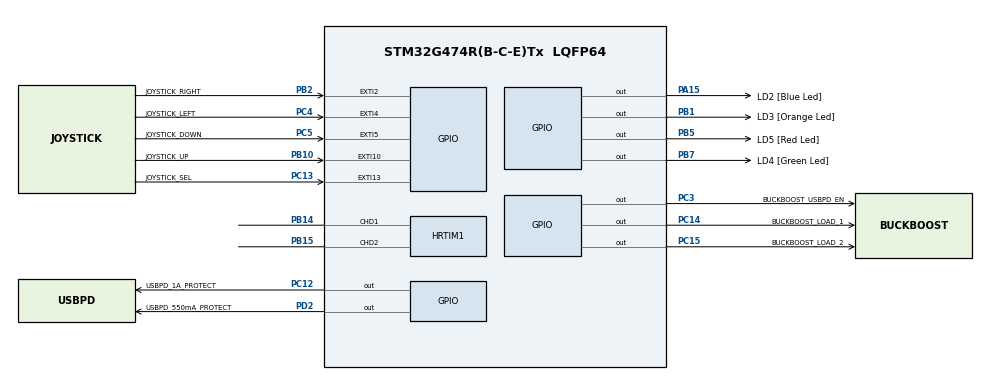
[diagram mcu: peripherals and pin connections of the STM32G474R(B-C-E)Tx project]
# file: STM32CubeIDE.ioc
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HRTIM1.CompareUnit1-Output_TD1TD2=HRTIM_COMPAREUNIT_1
HRTIM1.CompareUnit2-Output_TD1TD2=HRTIM_COMPAREUNIT_2
HRTIM1.CompareUnit3-Output_TD1TD2=HRTIM_COMPAREUNIT_3
HRTIM1.CompareValue1-Output_TD1TD2=544
HRTIM1.CompareValue2-Output_TD1TD2=544
HRTIM1.CompareValue3-Output_TD1TD2=1088
HRTIM1.NumberResetSource1-Output_TD1TD2=1
HRTIM1.NumberResetSource2_TD=1
HRTIM1.NumberSetSource1-Output_TD1TD2=1
HRTIM1.Periode_TD=5440
HRTIM1.ResetOutput1_Source1-Output_TD1TD2=HRTIM_OUTPUTRESET_TIMCMP1
HRTIM1.ResetOutput2_Source1-Output_TD1TD2=HRTIM_OUTPUTRESET_TIMCMP3
HRTIM1.SetOutput1_Source1-Output_TD1TD2=HRTIM_OUTPUTSET_TIMPER
Mcu.Family=STM32G4
Mcu.Name=STM32G474R(B-C-E)Tx
Mcu.Package=LQFP64
NVIC.EXTI15_10_IRQn=true\:0\:0\:false\:false\:true\:true\:true\:true
NVIC.EXTI2_IRQn=true\:0\:0\:false\:false\:true\:true\:true\:true
NVIC.EXTI4_IRQn=true\:0\:0\:false\:false\:true\:true\:true\:true
NVIC.EXTI9_5_IRQn=true\:0\:0\:false\:false\:true\:true\:true\:true
NVIC.PriorityGroup=NVIC_PRIORITYGROUP_4
PA0.GPIO_Label=BUCK_GREEN_SENSE
PA0.Signal=COMP3_INP
PA1.GPIO_Label=BUCKBOOST_VIN
PA1.Signal=ADC1_IN2
PA10.Signal=UCPD1_DBCC2
PA11.Signal=USB_DM
PA12.Signal=USB_DP
PA13.Mode=Serial_Wire
PA13.Signal=SYS_JTMS-SWDIO
PA14.Mode=Serial_Wire
PA14.Signal=SYS_JTCK-SWCLK
PA15.GPIO_Label=LD2 [Blue Led]
PA15.Signal=GPIO_Output
PA2.GPIO_Label=BUCKBOOST_I_IN_AVG
PA2.Signal=ADC1_IN3
PA3.GPIO_Label=BUCKBOOST_VOUT
PA3.Signal=ADC1_IN4
PA7.GPIO_Label=BUCK_RED_SENSE
PA7.Signal=COMP2_INP
PA8.GPIO_Label=BUCK_BLUE_DRIVE
PA8.Signal=HRTIM1_CHA1
PA9.Signal=UCPD1_DBCC1
PB0.GPIO_Label=BUCK_BLUE_SENSE
PB0.Signal=COMP4_INP
PB1.GPIO_Label=LD3 [Orange Led]
PB1.Signal=GPIO_Output
PB10.GPIO_Label=JOYSTICK_UP
PB10.GPIO_PuPd=GPIO_PULLUP
PB10.Signal=GPXTI10
PB11.GPIO_Label=BUCKBOOST_I_IN_SENSE
PB11.Signal=COMP6_INP
PB12.GPIO_Label=BUCKBOOST_P1_DRIVE
PB12.Signal=HRTIM1_CHC1
PB13.GPIO_Label=BUCKBOOST_N1_DRIVE
PB13.Signal=HRTIM1_CHC2
PB14.GPIO_Mode=GPIO_MODE_AF_PP
PB14.GPIO_PuPd=GPIO_NOPULL
PB14.GPIO_Speed_High_Default=GPIO_SPEED_FREQ_VERY_HIGH
PB14.Mode=Output_TD1TD2
PB14.Signal=HRTIM1_CHD1
PB15.Mode=Output_TD1TD2
PB15.Signal=HRTIM1_CHD2
PB2.GPIO_Label=JOYSTICK_RIGHT
PB2.GPIO_PuPd=GPIO_PULLUP
PB2.Signal=GPXTI2
PB3.Signal=SYS_JTDO-SWO
PB4.Signal=UCPD1_CC2
PB5.GPIO_Label=LD5 [Red Led]
PB5.Signal=GPIO_Output
PB6.Signal=UCPD1_CC1
PB7.GPIO_Label=LD4 [Green Led]
PB7.Signal=GPIO_Output
PC10.GPIO_Label=USART3_TX[STLINK_TX]
PC10.GPIO_Speed=GPIO_SPEED_FREQ_MEDIUM
PC10.Signal=USART3_TX
PC11.GPIO_Label=USART3_RX[STLINK_RX]
PC11.GPIO_Speed=GPIO_SPEED_FREQ_MEDIUM
PC11.Signal=USART3_RX
PC12.GPIO_Label=USBPD_1A_PROTECT
PC12.Signal=GPIO_Output
PC13.GPIO_Label=JOYSTICK_SEL
PC13.GPIO_PuPd=GPIO_PULLUP
PC13.Signal=GPXTI13
PC14-OSC32_IN.GPIO_Label=BUCKBOOST_LOAD_1
PC14-OSC32_IN.Signal=GPIO_Output
PC15-OSC32_OUT.GPIO_Label=BUCKBOOST_LOAD_2
PC15-OSC32_OUT.Signal=GPIO_Output
PC2.GPIO_Label=USBPD_VIN
PC2.Signal=ADC1_IN8
PC3.GPIO_Label=BUCKBOOST_USBPD_EN
PC3.Signal=GPIO_Output
PC4.GPIO_Label=JOYSTICK_LEFT
PC4.GPIO_PuPd=GPIO_PULLUP
PC4.Signal=GPXTI4
PC5.GPIO_Label=JOYSTICK_DOWN
PC5.GPIO_PuPd=GPIO_PULLUP
PC5.Signal=GPXTI5
PC6.GPIO_Label=BUCK_RED_DRIVE
PC6.Signal=HRTIM1_CHF1
PC7.GPIO_Label=RC_TP4
PC7.Signal=HRTIM1_CHF2
PC8.GPIO_Label=BUCK_GREEN_DRIVE
PC8.Signal=HRTIM1_CHE1
PD2.GPIO_Label=USBPD_550mA_PROTECT
PD2.Signal=GPIO_Output
ProjectManager.HeapSize=0x200
ProjectManager.StackSize=0x400
ProjectManager.TargetToolchain=STM32CubeIDE
RCC.ADC12Freq_Value=170000000
RCC.ADC345Freq_Value=170000000
RCC.AHBFreq_Value=170000000
RCC.APB1Freq_Value=170000000
RCC.APB1TimFreq_Value=170000000
RCC.APB2Freq_Value=170000000
RCC.APB2TimFreq_Value=170000000
RCC.CK48CLockSelection=RCC_USBCLKSOURCE_HSI48
RCC.CortexFreq_Value=170000000
RCC.EXTERNAL_CLOCK_VALUE=12288000
RCC.HCLKFreq_Value=170000000
RCC.HSE_VALUE=8000000
RCC.HSI48_VALUE=48000000
RCC.HSI_VALUE=16000000
RCC.LSE_VALUE=32768
RCC.PLLM=RCC_PLLM_DIV4
RCC.PLLN=85
RCC.PLLP=RCC_PLLP_DIV8
RCC.PLLQ=RCC_PLLQ_DIV8
RCC.SYSCLKFreq_VALUE=170000000
RCC.SYSCLKSource=RCC_SYSCLKSOURCE_PLLCLK
RCC.USBFreq_Value=48000000
RCC.VCOOutputFreq_Value=340000000
VP_SYS_VS_DBSignals.Mode=DisableDeadBatterySignals
board=B-G474E-DPOW1

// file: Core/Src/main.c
/* USER CODE BEGIN Header */
/**
  ******************************************************************************
  * @file           : main.c
  * @brief          : Main program body
  ******************************************************************************
  * @attention
  *
  * Copyright (c) 2026 STMicroelectronics.
  * All rights reserved.
  *
  * This software is licensed under terms that can be found in the LICENSE file
  * in the root directory of this software component.
  * If no LICENSE file comes with this software, it is provided AS-IS.
  *
  ******************************************************************************
  */
/* USER CODE END Header */
#include "main.h"

/* USER CODE BEGIN PD */
/*
 * Timing profile:
 * - HRTIM_TIMING_PROFILE_MAX_RES: 170 MHz x 32 = 183.824 ps/tick
 * - HRTIM_TIMING_PROFILE_500PS:   125 MHz x 16 = 500 ps/tick
 * - HRTIM_TIMING_PROFILE_250PS:   125 MHz x 32 = 250 ps/tick
 */
#define HRTIM_TIMING_PROFILE_MAX_RES  0U
#define HRTIM_TIMING_PROFILE_500PS    1U
#define HRTIM_TIMING_PROFILE_250PS    2U
#define HRTIM_TIMING_PROFILE          HRTIM_TIMING_PROFILE_500PS

#if (HRTIM_TIMING_PROFILE == HRTIM_TIMING_PROFILE_MAX_RES)
#define HRTIM_PLLN_VALUE        85U
#define HRTIM_PLLR_VALUE        RCC_PLLR_DIV2
#define HRTIM_TIMER_PRESCALER   HRTIM_PRESCALERRATIO_MUL32
#define HRTIM_PERIOD_TICK       5440U
#define HRTIM_100NS_TICK        544U
#elif (HRTIM_TIMING_PROFILE == HRTIM_TIMING_PROFILE_500PS)
#define HRTIM_PLLN_VALUE        125U
#define HRTIM_PLLR_VALUE        RCC_PLLR_DIV4
#define HRTIM_TIMER_PRESCALER   HRTIM_PRESCALERRATIO_MUL16
#define HRTIM_PERIOD_TICK       2000U
#define HRTIM_100NS_TICK        200U
#elif (HRTIM_TIMING_PROFILE == HRTIM_TIMING_PROFILE_250PS)
#define HRTIM_PLLN_VALUE        125U
#define HRTIM_PLLR_VALUE        RCC_PLLR_DIV4
#define HRTIM_TIMER_PRESCALER   HRTIM_PRESCALERRATIO_MUL32
#define HRTIM_PERIOD_TICK       4000U
#define HRTIM_100NS_TICK        400U
#else
#error "Unsupported HRTIM_TIMING_PROFILE"
#endif

#define TD1_WIDTH_TICK          HRTIM_100NS_TICK
#define TD1_RISE_TICK           ((HRTIM_PERIOD_TICK / 2U) - (TD1_WIDTH_TICK / 2U))
#define TD1_FALL_TICK           (TD1_RISE_TICK + TD1_WIDTH_TICK)
#define TD2_WIDTH_TICK          TD1_WIDTH_TICK
#define TD2_DELAY_INITIAL_TICK  0U
#define TD2_DELAY_STEP_TICK     1U
#define TD2_DELAY_MAX_TICK      (HRTIM_PERIOD_TICK - TD1_FALL_TICK - TD2_WIDTH_TICK)
#define JOYSTICK_DEBOUNCE_MS    200U
#define JOYSTICK_SETTLE_MS      2U
/* USER CODE END PD */

HRTIM_HandleTypeDef hhrtim1;

/* USER CODE BEGIN PV */
static volatile uint16_t td2_delay_tick = TD2_DELAY_INITIAL_TICK;
static volatile int8_t pending_delay_step = 0;
static volatile uint8_t pending_delay_reset = 0U;
/* USER CODE END PV */

void SystemClock_Config(void);
static void MX_GPIO_Init(void);
static void MX_HRTIM1_Init(void);
/* USER CODE BEGIN PFP */
static void Apply_TD2_Delay(void);
static void Process_Joystick_Command(void);
/* USER CODE END PFP */

/* USER CODE BEGIN 0 */
static void Apply_TD2_Delay(void)
{
  uint32_t cmp3 = TD1_FALL_TICK + td2_delay_tick;
  uint32_t cmp4 = cmp3 + TD2_WIDTH_TICK;

  __HAL_HRTIM_SETCOMPARE(&hhrtim1, HRTIM_TIMERINDEX_TIMER_D, HRTIM_COMPAREUNIT_3, cmp3);
  __HAL_HRTIM_SETCOMPARE(&hhrtim1, HRTIM_TIMERINDEX_TIMER_D, HRTIM_COMPAREUNIT_4, cmp4);
}

static void Process_Joystick_Command(void)
{
  int8_t step;
  uint8_t reset;

  __disable_irq();
  step = pending_delay_step;
  reset = pending_delay_reset;
  pending_delay_step = 0;
  pending_delay_reset = 0U;
  __enable_irq();

  if (reset != 0U)
  {
    td2_delay_tick = TD2_DELAY_INITIAL_TICK;
    Apply_TD2_Delay();
    HAL_Delay(JOYSTICK_SETTLE_MS);
    return;
  }

  if (step > 0)
  {
    if ((td2_delay_tick + TD2_DELAY_STEP_TICK) < TD2_DELAY_MAX_TICK)
    {
      td2_delay_tick += TD2_DELAY_STEP_TICK;
    }
    else
    {
      td2_delay_tick = TD2_DELAY_MAX_TICK;
    }
    Apply_TD2_Delay();
    HAL_Delay(JOYSTICK_SETTLE_MS);
  }
  else if (step < 0)
  {
    if (td2_delay_tick > TD2_DELAY_STEP_TICK)
    {
      td2_delay_tick -= TD2_DELAY_STEP_TICK;
    }
    else
    {
      td2_delay_tick = 0U;
    }
    Apply_TD2_Delay();
    HAL_Delay(JOYSTICK_SETTLE_MS);
  }
}
/* USER CODE END 0 */

int main(void)
{

  /* MCU Configuration--------------------------------------------------------*/

  /* Reset of all peripherals, Initializes the Flash interface and the Systick. */
  HAL_Init();

  /* Configure the system clock */
  SystemClock_Config();

  /* Initialize all configured peripherals */
  MX_GPIO_Init();
  MX_HRTIM1_Init();
  /* USER CODE BEGIN 2 */
  if (HAL_HRTIM_WaveformOutputStart(&hhrtim1, HRTIM_OUTPUT_TD1 | HRTIM_OUTPUT_TD2) != HAL_OK)
  {
    Error_Handler();
  }
  if (HAL_HRTIM_WaveformCountStart(&hhrtim1, HRTIM_TIMERID_TIMER_D) != HAL_OK)
  {
    Error_Handler();
  }
  /* USER CODE END 2 */

  /* Infinite loop */
  while (1)
  {

    /* USER CODE BEGIN 3 */
    Process_Joystick_Command();
  }
  /* USER CODE END 3 */
}

void SystemClock_Config(void)
{
  RCC_OscInitTypeDef RCC_OscInitStruct = {0};
  RCC_ClkInitTypeDef RCC_ClkInitStruct = {0};

  /** Configure the main internal regulator output voltage
  */
  HAL_PWREx_ControlVoltageScaling(PWR_REGULATOR_VOLTAGE_SCALE1_BOOST);

  /** Initializes the RCC Oscillators according to the specified parameters
  * in the RCC_OscInitTypeDef structure.
  */
  RCC_OscInitStruct.OscillatorType = RCC_OSCILLATORTYPE_HSI;
  RCC_OscInitStruct.HSIState = RCC_HSI_ON;
  RCC_OscInitStruct.HSICalibrationValue = RCC_HSICALIBRATION_DEFAULT;
  RCC_OscInitStruct.PLL.PLLState = RCC_PLL_ON;
  RCC_OscInitStruct.PLL.PLLSource = RCC_PLLSOURCE_HSI;
  RCC_OscInitStruct.PLL.PLLM = RCC_PLLM_DIV4;
  RCC_OscInitStruct.PLL.PLLN = HRTIM_PLLN_VALUE;
  RCC_OscInitStruct.PLL.PLLP = RCC_PLLP_DIV8;
  RCC_OscInitStruct.PLL.PLLQ = RCC_PLLQ_DIV8;
  RCC_OscInitStruct.PLL.PLLR = HRTIM_PLLR_VALUE;
  if (HAL_RCC_OscConfig(&RCC_OscInitStruct) != HAL_OK)
  {
    Error_Handler();
  }

  /** Initializes the CPU, AHB and APB buses clocks
  */
  RCC_ClkInitStruct.ClockType = RCC_CLOCKTYPE_HCLK|RCC_CLOCKTYPE_SYSCLK
                              |RCC_CLOCKTYPE_PCLK1|RCC_CLOCKTYPE_PCLK2;
  RCC_ClkInitStruct.SYSCLKSource = RCC_SYSCLKSOURCE_PLLCLK;
  RCC_ClkInitStruct.AHBCLKDivider = RCC_SYSCLK_DIV1;
  RCC_ClkInitStruct.APB1CLKDivider = RCC_HCLK_DIV1;
  RCC_ClkInitStruct.APB2CLKDivider = RCC_HCLK_DIV1;

  if (HAL_RCC_ClockConfig(&RCC_ClkInitStruct, FLASH_LATENCY_4) != HAL_OK)
  {
    Error_Handler();
  }
}

static void MX_HRTIM1_Init(void)
{

  HRTIM_TimeBaseCfgTypeDef pTimeBaseCfg = {0};
  HRTIM_TimerCtlTypeDef pTimerCtl = {0};
  HRTIM_TimerCfgTypeDef pTimerCfg = {0};
  HRTIM_CompareCfgTypeDef pCompareCfg = {0};
  HRTIM_OutputCfgTypeDef pOutputCfg = {0};

  hhrtim1.Instance = HRTIM1;
  hhrtim1.Init.HRTIMInterruptResquests = HRTIM_IT_NONE;
  hhrtim1.Init.SyncOptions = HRTIM_SYNCOPTION_NONE;
  if (HAL_HRTIM_Init(&hhrtim1) != HAL_OK)
  {
    Error_Handler();
  }
  if (HAL_HRTIM_DLLCalibrationStart(&hhrtim1, HRTIM_CALIBRATIONRATE_3) != HAL_OK)
  {
    Error_Handler();
  }
  if (HAL_HRTIM_PollForDLLCalibration(&hhrtim1, 10) != HAL_OK)
  {
    Error_Handler();
  }
  pTimeBaseCfg.Period = HRTIM_PERIOD_TICK;
  pTimeBaseCfg.RepetitionCounter = 0x00;
  pTimeBaseCfg.PrescalerRatio = HRTIM_TIMER_PRESCALER;
  pTimeBaseCfg.Mode = HRTIM_MODE_CONTINUOUS;
  if (HAL_HRTIM_TimeBaseConfig(&hhrtim1, HRTIM_TIMERINDEX_TIMER_D, &pTimeBaseCfg) != HAL_OK)
  {
    Error_Handler();
  }
  pTimerCtl.UpDownMode = HRTIM_TIMERUPDOWNMODE_UP;
  pTimerCtl.TrigHalf = HRTIM_TIMERTRIGHALF_DISABLED;
  pTimerCtl.GreaterCMP3 = HRTIM_TIMERGTCMP3_EQUAL;
  pTimerCtl.GreaterCMP1 = HRTIM_TIMERGTCMP1_EQUAL;
  pTimerCtl.DualChannelDacEnable = HRTIM_TIMER_DCDE_DISABLED;
  if (HAL_HRTIM_WaveformTimerControl(&hhrtim1, HRTIM_TIMERINDEX_TIMER_D, &pTimerCtl) != HAL_OK)
  {
    Error_Handler();
  }
  pTimerCfg.InterruptRequests = HRTIM_TIM_IT_NONE;
  pTimerCfg.DMARequests = HRTIM_TIM_DMA_NONE;
  pTimerCfg.DMASrcAddress = 0x0000;
  pTimerCfg.DMADstAddress = 0x0000;
  pTimerCfg.DMASize = 0x1;
  pTimerCfg.HalfModeEnable = HRTIM_HALFMODE_DISABLED;
  pTimerCfg.InterleavedMode = HRTIM_INTERLEAVED_MODE_DISABLED;
  pTimerCfg.StartOnSync = HRTIM_SYNCSTART_DISABLED;
  pTimerCfg.ResetOnSync = HRTIM_SYNCRESET_DISABLED;
  pTimerCfg.DACSynchro = HRTIM_DACSYNC_NONE;
  pTimerCfg.PreloadEnable = HRTIM_PRELOAD_DISABLED;
  pTimerCfg.UpdateGating = HRTIM_UPDATEGATING_INDEPENDENT;
  pTimerCfg.BurstMode = HRTIM_TIMERBURSTMODE_MAINTAINCLOCK;
  pTimerCfg.RepetitionUpdate = HRTIM_UPDATEONREPETITION_DISABLED;
  pTimerCfg.PushPull = HRTIM_TIMPUSHPULLMODE_DISABLED;
  pTimerCfg.FaultEnable = HRTIM_TIMFAULTENABLE_NONE;
  pTimerCfg.FaultLock = HRTIM_TIMFAULTLOCK_READWRITE;
  pTimerCfg.DeadTimeInsertion = HRTIM_TIMDEADTIMEINSERTION_DISABLED;
  pTimerCfg.DelayedProtectionMode = HRTIM_TIMER_D_E_DELAYEDPROTECTION_DISABLED;
  pTimerCfg.UpdateTrigger = HRTIM_TIMUPDATETRIGGER_NONE;
  pTimerCfg.ResetTrigger = HRTIM_TIMRESETTRIGGER_NONE;
  pTimerCfg.ResetUpdate = HRTIM_TIMUPDATEONRESET_DISABLED;
  pTimerCfg.ReSyncUpdate = HRTIM_TIMERESYNC_UPDATE_UNCONDITIONAL;
  if (HAL_HRTIM_WaveformTimerConfig(&hhrtim1, HRTIM_TIMERINDEX_TIMER_D, &pTimerCfg) != HAL_OK)
  {
    Error_Handler();
  }
  pCompareCfg.CompareValue = TD1_RISE_TICK;
  if (HAL_HRTIM_WaveformCompareConfig(&hhrtim1, HRTIM_TIMERINDEX_TIMER_D, HRTIM_COMPAREUNIT_1, &pCompareCfg) != HAL_OK)
  {
    Error_Handler();
  }
  pCompareCfg.AutoDelayedMode = HRTIM_AUTODELAYEDMODE_REGULAR;
  pCompareCfg.AutoDelayedTimeout = 0x0000;
  pCompareCfg.CompareValue = TD1_FALL_TICK;

  if (HAL_HRTIM_WaveformCompareConfig(&hhrtim1, HRTIM_TIMERINDEX_TIMER_D, HRTIM_COMPAREUNIT_2, &pCompareCfg) != HAL_OK)
  {
    Error_Handler();
  }
  pCompareCfg.CompareValue = TD1_FALL_TICK + td2_delay_tick;
  if (HAL_HRTIM_WaveformCompareConfig(&hhrtim1, HRTIM_TIMERINDEX_TIMER_D, HRTIM_COMPAREUNIT_3, &pCompareCfg) != HAL_OK)
  {
    Error_Handler();
  }
  pCompareCfg.CompareValue = TD1_FALL_TICK + td2_delay_tick + TD2_WIDTH_TICK;
  if (HAL_HRTIM_WaveformCompareConfig(&hhrtim1, HRTIM_TIMERINDEX_TIMER_D, HRTIM_COMPAREUNIT_4, &pCompareCfg) != HAL_OK)
  {
    Error_Handler();
  }
  pOutputCfg.Polarity = HRTIM_OUTPUTPOLARITY_HIGH;
  pOutputCfg.SetSource = HRTIM_OUTPUTSET_TIMCMP1;
  pOutputCfg.ResetSource = HRTIM_OUTPUTRESET_TIMCMP2;
  pOutputCfg.IdleMode = HRTIM_OUTPUTIDLEMODE_NONE;
  pOutputCfg.IdleLevel = HRTIM_OUTPUTIDLELEVEL_INACTIVE;
  pOutputCfg.FaultLevel = HRTIM_OUTPUTFAULTLEVEL_NONE;
  pOutputCfg.ChopperModeEnable = HRTIM_OUTPUTCHOPPERMODE_DISABLED;
  pOutputCfg.BurstModeEntryDelayed = HRTIM_OUTPUTBURSTMODEENTRY_REGULAR;
  if (HAL_HRTIM_WaveformOutputConfig(&hhrtim1, HRTIM_TIMERINDEX_TIMER_D, HRTIM_OUTPUT_TD1, &pOutputCfg) != HAL_OK)
  {
    Error_Handler();
  }
  pOutputCfg.SetSource = HRTIM_OUTPUTSET_NONE;
  pOutputCfg.ResetSource = HRTIM_OUTPUTRESET_TIMCMP3;
  if (HAL_HRTIM_WaveformOutputConfig(&hhrtim1, HRTIM_TIMERINDEX_TIMER_D, HRTIM_OUTPUT_TD2, &pOutputCfg) != HAL_OK)
  {
    Error_Handler();
  }
  /* USER CODE BEGIN HRTIM1_Init 2 */
  pOutputCfg.SetSource = HRTIM_OUTPUTSET_TIMCMP3;
  pOutputCfg.ResetSource = HRTIM_OUTPUTRESET_TIMCMP4;
  if (HAL_HRTIM_WaveformOutputConfig(&hhrtim1, HRTIM_TIMERINDEX_TIMER_D, HRTIM_OUTPUT_TD2, &pOutputCfg) != HAL_OK)
  {
    Error_Handler();
  }
  /* USER CODE END HRTIM1_Init 2 */
  HAL_HRTIM_MspPostInit(&hhrtim1);

}

static void MX_GPIO_Init(void)
{
  GPIO_InitTypeDef GPIO_InitStruct = {0};

  /* GPIO Ports Clock Enable */
  __HAL_RCC_GPIOC_CLK_ENABLE();
  __HAL_RCC_GPIOA_CLK_ENABLE();
  __HAL_RCC_GPIOB_CLK_ENABLE();
  __HAL_RCC_GPIOD_CLK_ENABLE();

  /*Configure GPIO pin Output Level */
  HAL_GPIO_WritePin(GPIOC, BUCKBOOST_LOAD_1_Pin|BUCKBOOST_LOAD_2_Pin|BUCKBOOST_USBPD_EN_Pin|USBPD_1A_PROTECT_Pin, GPIO_PIN_RESET);

  /*Configure GPIO pin Output Level */
  HAL_GPIO_WritePin(GPIOB, LD3_Pin|LD5_Pin|LD4_Pin, GPIO_PIN_RESET);

  /*Configure GPIO pin Output Level */
  HAL_GPIO_WritePin(LD2_GPIO_Port, LD2_Pin, GPIO_PIN_RESET);

  /*Configure GPIO pin Output Level */
  HAL_GPIO_WritePin(USBPD_550mA_PROTECT_GPIO_Port, USBPD_550mA_PROTECT_Pin, GPIO_PIN_RESET);

  /*Configure GPIO pins : JOYSTICK_SEL_Pin JOYSTICK_LEFT_Pin JOYSTICK_DOWN_Pin */
  GPIO_InitStruct.Pin = JOYSTICK_SEL_Pin|JOYSTICK_LEFT_Pin|JOYSTICK_DOWN_Pin;
  GPIO_InitStruct.Mode = GPIO_MODE_IT_RISING;
  GPIO_InitStruct.Pull = GPIO_PULLUP;
  HAL_GPIO_Init(GPIOC, &GPIO_InitStruct);

  /*Configure GPIO pins : BUCKBOOST_LOAD_1_Pin BUCKBOOST_LOAD_2_Pin BUCKBOOST_USBPD_EN_Pin USBPD_1A_PROTECT_Pin */
  GPIO_InitStruct.Pin = BUCKBOOST_LOAD_1_Pin|BUCKBOOST_LOAD_2_Pin|BUCKBOOST_USBPD_EN_Pin|USBPD_1A_PROTECT_Pin;
  GPIO_InitStruct.Mode = GPIO_MODE_OUTPUT_PP;
  GPIO_InitStruct.Pull = GPIO_NOPULL;
  GPIO_InitStruct.Speed = GPIO_SPEED_FREQ_LOW;
  HAL_GPIO_Init(GPIOC, &GPIO_InitStruct);

  /*Configure GPIO pin : USBPD_VIN_Pin */
  GPIO_InitStruct.Pin = USBPD_VIN_Pin;
  GPIO_InitStruct.Mode = GPIO_MODE_ANALOG;
  GPIO_InitStruct.Pull = GPIO_NOPULL;
  HAL_GPIO_Init(USBPD_VIN_GPIO_Port, &GPIO_InitStruct);

  /*Configure GPIO pins : BUCK_GREEN_SENSE_Pin BUCKBOOST_VIN_Pin BUCKBOOST_I_IN_AVG_Pin BUCKBOOST_VOUT_Pin
                           BUCK_RED_SENSE_Pin */
  GPIO_InitStruct.Pin = BUCK_GREEN_SENSE_Pin|BUCKBOOST_VIN_Pin|BUCKBOOST_I_IN_AVG_Pin|BUCKBOOST_VOUT_Pin
                          |BUCK_RED_SENSE_Pin;
  GPIO_InitStruct.Mode = GPIO_MODE_ANALOG;
  GPIO_InitStruct.Pull = GPIO_NOPULL;
  HAL_GPIO_Init(GPIOA, &GPIO_InitStruct);

  /*Configure GPIO pins : BUCK_BLUE_SENSE_Pin BUCKBOOST_I_IN_SENSE_Pin PB4 PB6 */
  GPIO_InitStruct.Pin = BUCK_BLUE_SENSE_Pin|BUCKBOOST_I_IN_SENSE_Pin|GPIO_PIN_4|GPIO_PIN_6;
  GPIO_InitStruct.Mode = GPIO_MODE_ANALOG;
  GPIO_InitStruct.Pull = GPIO_NOPULL;
  HAL_GPIO_Init(GPIOB, &GPIO_InitStruct);

  /*Configure GPIO pins : LD3_Pin LD5_Pin LD4_Pin */
  GPIO_InitStruct.Pin = LD3_Pin|LD5_Pin|LD4_Pin;
  GPIO_InitStruct.Mode = GPIO_MODE_OUTPUT_PP;
  GPIO_InitStruct.Pull = GPIO_NOPULL;
  GPIO_InitStruct.Speed = GPIO_SPEED_FREQ_LOW;
  HAL_GPIO_Init(GPIOB, &GPIO_InitStruct);

  /*Configure GPIO pins : JOYSTICK_RIGHT_Pin JOYSTICK_UP_Pin */
  GPIO_InitStruct.Pin = JOYSTICK_RIGHT_Pin|JOYSTICK_UP_Pin;
  GPIO_InitStruct.Mode = GPIO_MODE_IT_RISING;
  GPIO_InitStruct.Pull = GPIO_PULLUP;
  HAL_GPIO_Init(GPIOB, &GPIO_InitStruct);

  /*Configure GPIO pin : LD2_Pin */
  GPIO_InitStruct.Pin = LD2_Pin;
  GPIO_InitStruct.Mode = GPIO_MODE_OUTPUT_PP;
  GPIO_InitStruct.Pull = GPIO_NOPULL;
  GPIO_InitStruct.Speed = GPIO_SPEED_FREQ_LOW;
  HAL_GPIO_Init(LD2_GPIO_Port, &GPIO_InitStruct);

  /*Configure GPIO pins : USART3_TX_Pin USART3_RX_Pin */
  GPIO_InitStruct.Pin = USART3_TX_Pin|USART3_RX_Pin;
  GPIO_InitStruct.Mode = GPIO_MODE_AF_PP;
  GPIO_InitStruct.Pull = GPIO_NOPULL;
  GPIO_InitStruct.Speed = GPIO_SPEED_FREQ_MEDIUM;
  GPIO_InitStruct.Alternate = GPIO_AF7_USART3;
  HAL_GPIO_Init(GPIOC, &GPIO_InitStruct);

  /*Configure GPIO pin : USBPD_550mA_PROTECT_Pin */
  GPIO_InitStruct.Pin = USBPD_550mA_PROTECT_Pin;
  GPIO_InitStruct.Mode = GPIO_MODE_OUTPUT_PP;
  GPIO_InitStruct.Pull = GPIO_NOPULL;
  GPIO_InitStruct.Speed = GPIO_SPEED_FREQ_LOW;
  HAL_GPIO_Init(USBPD_550mA_PROTECT_GPIO_Port, &GPIO_InitStruct);

  /* EXTI interrupt init*/
  HAL_NVIC_SetPriority(EXTI2_IRQn, 0, 0);
  HAL_NVIC_EnableIRQ(EXTI2_IRQn);

  HAL_NVIC_SetPriority(EXTI4_IRQn, 0, 0);
  HAL_NVIC_EnableIRQ(EXTI4_IRQn);

  HAL_NVIC_SetPriority(EXTI9_5_IRQn, 0, 0);
  HAL_NVIC_EnableIRQ(EXTI9_5_IRQn);

  HAL_NVIC_SetPriority(EXTI15_10_IRQn, 0, 0);
  HAL_NVIC_EnableIRQ(EXTI15_10_IRQn);

}

/* USER CODE BEGIN 4 */
void HAL_GPIO_EXTI_Callback(uint16_t GPIO_Pin)
{
  static uint32_t last_joystick_ms = 0U;
  uint32_t now = HAL_GetTick();

  if ((now - last_joystick_ms) < JOYSTICK_DEBOUNCE_MS)
  {
    return;
  }
  last_joystick_ms = now;

  if ((GPIO_Pin == JOYSTICK_RIGHT_Pin) || (GPIO_Pin == JOYSTICK_DOWN_Pin))
  {
    pending_delay_step = 1;
  }
  else if ((GPIO_Pin == JOYSTICK_LEFT_Pin) || (GPIO_Pin == JOYSTICK_UP_Pin))
  {
    pending_delay_step = -1;
  }
  else if (GPIO_Pin == JOYSTICK_SEL_Pin)
  {
    pending_delay_reset = 1U;
  }
}
/* USER CODE END 4 */

void Error_Handler(void)
{
  __disable_irq();
  while (1)
  {
  }
}
